##
## LEF for PtnCells ;
## created by Innovus v15.23-s045_1 on Tue Mar 10 18:08:15 2026
##

VERSION 5.8 ;

BUSBITCHARS "[]" ;
DIVIDERCHAR "/" ;

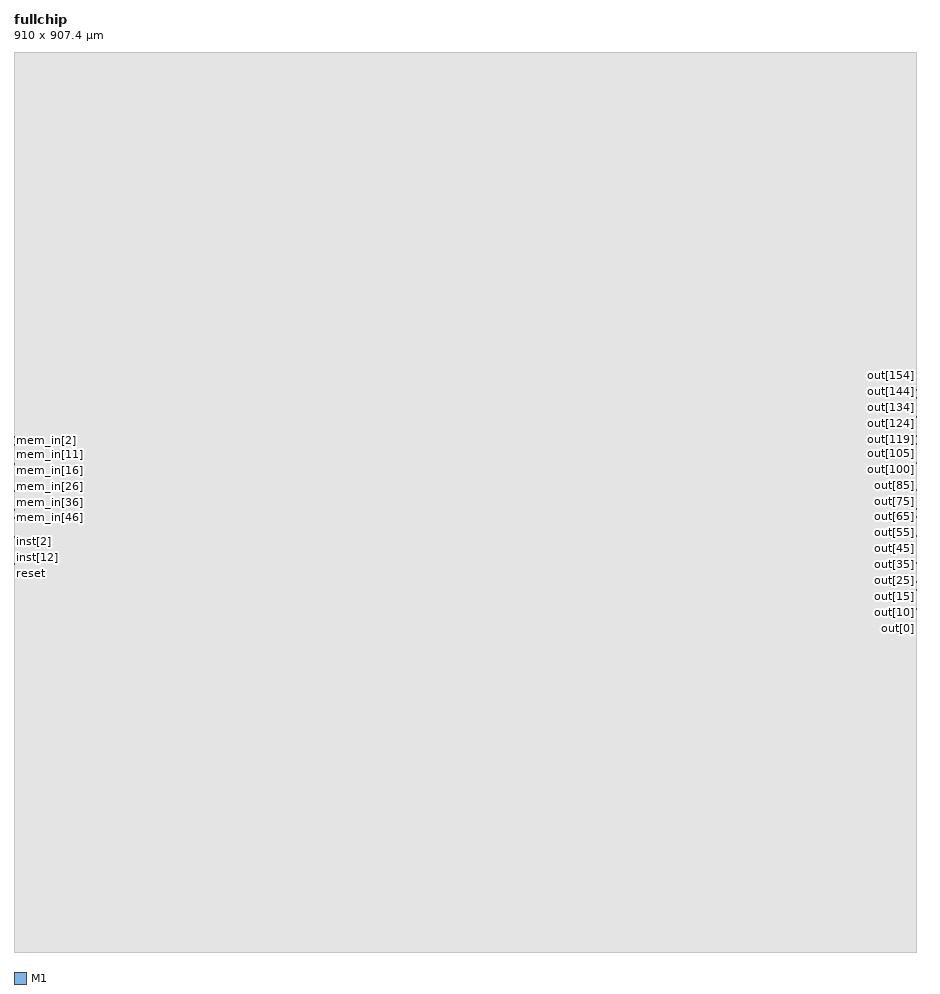
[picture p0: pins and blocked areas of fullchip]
MACRO fullchip
  CLASS BLOCK ;
  SIZE 910.0000 BY 907.4000 ;
  FOREIGN fullchip 0.0000 0.0000 ;
  ORIGIN 0 0 ;
  SYMMETRY X Y R90 ;
  PIN clk
    DIRECTION INPUT ;
    USE SIGNAL ;
    PORT
      LAYER M1 ;
        RECT 0.0000 387.9550 0.4700 388.0450 ;
    END
  END clk
  PIN mem_in[63]
    DIRECTION INPUT ;
    USE SIGNAL ;
    PORT
      LAYER M1 ;
        RECT 0.0000 418.3550 0.4700 418.4450 ;
    END
  END mem_in[63]
  PIN mem_in[62]
    DIRECTION INPUT ;
    USE SIGNAL ;
    PORT
      LAYER M1 ;
        RECT 0.0000 419.9550 0.4700 420.0450 ;
    END
  END mem_in[62]
  PIN mem_in[61]
    DIRECTION INPUT ;
    USE SIGNAL ;
    PORT
      LAYER M1 ;
        RECT 0.0000 421.5550 0.4700 421.6450 ;
    END
  END mem_in[61]
  PIN mem_in[60]
    DIRECTION INPUT ;
    USE SIGNAL ;
    PORT
      LAYER M1 ;
        RECT 0.0000 423.1550 0.4700 423.2450 ;
    END
  END mem_in[60]
  PIN mem_in[59]
    DIRECTION INPUT ;
    USE SIGNAL ;
    PORT
      LAYER M1 ;
        RECT 0.0000 424.7550 0.4700 424.8450 ;
    END
  END mem_in[59]
  PIN mem_in[58]
    DIRECTION INPUT ;
    USE SIGNAL ;
    PORT
      LAYER M1 ;
        RECT 0.0000 426.3550 0.4700 426.4450 ;
    END
  END mem_in[58]
  PIN mem_in[57]
    DIRECTION INPUT ;
    USE SIGNAL ;
    PORT
      LAYER M1 ;
        RECT 0.0000 427.9550 0.4700 428.0450 ;
    END
  END mem_in[57]
  PIN mem_in[56]
    DIRECTION INPUT ;
    USE SIGNAL ;
    PORT
      LAYER M1 ;
        RECT 0.0000 429.5550 0.4700 429.6450 ;
    END
  END mem_in[56]
  PIN mem_in[55]
    DIRECTION INPUT ;
    USE SIGNAL ;
    PORT
      LAYER M1 ;
        RECT 0.0000 431.1550 0.4700 431.2450 ;
    END
  END mem_in[55]
  PIN mem_in[54]
    DIRECTION INPUT ;
    USE SIGNAL ;
    PORT
      LAYER M1 ;
        RECT 0.0000 432.7550 0.4700 432.8450 ;
    END
  END mem_in[54]
  PIN mem_in[53]
    DIRECTION INPUT ;
    USE SIGNAL ;
    PORT
      LAYER M1 ;
        RECT 0.0000 434.3550 0.4700 434.4450 ;
    END
  END mem_in[53]
  PIN mem_in[52]
    DIRECTION INPUT ;
    USE SIGNAL ;
    PORT
      LAYER M1 ;
        RECT 0.0000 435.9550 0.4700 436.0450 ;
    END
  END mem_in[52]
  PIN mem_in[51]
    DIRECTION INPUT ;
    USE SIGNAL ;
    PORT
      LAYER M1 ;
        RECT 0.0000 437.5550 0.4700 437.6450 ;
    END
  END mem_in[51]
  PIN mem_in[50]
    DIRECTION INPUT ;
    USE SIGNAL ;
    PORT
      LAYER M1 ;
        RECT 0.0000 439.1550 0.4700 439.2450 ;
    END
  END mem_in[50]
  PIN mem_in[49]
    DIRECTION INPUT ;
    USE SIGNAL ;
    PORT
      LAYER M1 ;
        RECT 0.0000 440.7550 0.4700 440.8450 ;
    END
  END mem_in[49]
  PIN mem_in[48]
    DIRECTION INPUT ;
    USE SIGNAL ;
    PORT
      LAYER M1 ;
        RECT 0.0000 442.3550 0.4700 442.4450 ;
    END
  END mem_in[48]
  PIN mem_in[47]
    DIRECTION INPUT ;
    USE SIGNAL ;
    PORT
      LAYER M1 ;
        RECT 0.0000 443.9550 0.4700 444.0450 ;
    END
  END mem_in[47]
  PIN mem_in[46]
    DIRECTION INPUT ;
    USE SIGNAL ;
    PORT
      LAYER M1 ;
        RECT 0.0000 445.5550 0.4700 445.6450 ;
    END
  END mem_in[46]
  PIN mem_in[45]
    DIRECTION INPUT ;
    USE SIGNAL ;
    PORT
      LAYER M1 ;
        RECT 0.0000 447.1550 0.4700 447.2450 ;
    END
  END mem_in[45]
  PIN mem_in[44]
    DIRECTION INPUT ;
    USE SIGNAL ;
    PORT
      LAYER M1 ;
        RECT 0.0000 448.7550 0.4700 448.8450 ;
    END
  END mem_in[44]
  PIN mem_in[43]
    DIRECTION INPUT ;
    USE SIGNAL ;
    PORT
      LAYER M1 ;
        RECT 0.0000 450.3550 0.4700 450.4450 ;
    END
  END mem_in[43]
  PIN mem_in[42]
    DIRECTION INPUT ;
    USE SIGNAL ;
    PORT
      LAYER M1 ;
        RECT 0.0000 451.9550 0.4700 452.0450 ;
    END
  END mem_in[42]
  PIN mem_in[41]
    DIRECTION INPUT ;
    USE SIGNAL ;
    PORT
      LAYER M1 ;
        RECT 0.0000 453.5550 0.4700 453.6450 ;
    END
  END mem_in[41]
  PIN mem_in[40]
    DIRECTION INPUT ;
    USE SIGNAL ;
    PORT
      LAYER M1 ;
        RECT 0.0000 455.1550 0.4700 455.2450 ;
    END
  END mem_in[40]
  PIN mem_in[39]
    DIRECTION INPUT ;
    USE SIGNAL ;
    PORT
      LAYER M1 ;
        RECT 0.0000 456.7550 0.4700 456.8450 ;
    END
  END mem_in[39]
  PIN mem_in[38]
    DIRECTION INPUT ;
    USE SIGNAL ;
    PORT
      LAYER M1 ;
        RECT 0.0000 458.3550 0.4700 458.4450 ;
    END
  END mem_in[38]
  PIN mem_in[37]
    DIRECTION INPUT ;
    USE SIGNAL ;
    PORT
      LAYER M1 ;
        RECT 0.0000 459.9550 0.4700 460.0450 ;
    END
  END mem_in[37]
  PIN mem_in[36]
    DIRECTION INPUT ;
    USE SIGNAL ;
    PORT
      LAYER M1 ;
        RECT 0.0000 461.5550 0.4700 461.6450 ;
    END
  END mem_in[36]
  PIN mem_in[35]
    DIRECTION INPUT ;
    USE SIGNAL ;
    PORT
      LAYER M1 ;
        RECT 0.0000 463.1550 0.4700 463.2450 ;
    END
  END mem_in[35]
  PIN mem_in[34]
    DIRECTION INPUT ;
    USE SIGNAL ;
    PORT
      LAYER M1 ;
        RECT 0.0000 464.7550 0.4700 464.8450 ;
    END
  END mem_in[34]
  PIN mem_in[33]
    DIRECTION INPUT ;
    USE SIGNAL ;
    PORT
      LAYER M1 ;
        RECT 0.0000 466.3550 0.4700 466.4450 ;
    END
  END mem_in[33]
  PIN mem_in[32]
    DIRECTION INPUT ;
    USE SIGNAL ;
    PORT
      LAYER M1 ;
        RECT 0.0000 467.9550 0.4700 468.0450 ;
    END
  END mem_in[32]
  PIN mem_in[31]
    DIRECTION INPUT ;
    USE SIGNAL ;
    PORT
      LAYER M1 ;
        RECT 0.0000 469.5550 0.4700 469.6450 ;
    END
  END mem_in[31]
  PIN mem_in[30]
    DIRECTION INPUT ;
    USE SIGNAL ;
    PORT
      LAYER M1 ;
        RECT 0.0000 471.1550 0.4700 471.2450 ;
    END
  END mem_in[30]
  PIN mem_in[29]
    DIRECTION INPUT ;
    USE SIGNAL ;
    PORT
      LAYER M1 ;
        RECT 0.0000 472.7550 0.4700 472.8450 ;
    END
  END mem_in[29]
  PIN mem_in[28]
    DIRECTION INPUT ;
    USE SIGNAL ;
    PORT
      LAYER M1 ;
        RECT 0.0000 474.3550 0.4700 474.4450 ;
    END
  END mem_in[28]
  PIN mem_in[27]
    DIRECTION INPUT ;
    USE SIGNAL ;
    PORT
      LAYER M1 ;
        RECT 0.0000 475.9550 0.4700 476.0450 ;
    END
  END mem_in[27]
  PIN mem_in[26]
    DIRECTION INPUT ;
    USE SIGNAL ;
    PORT
      LAYER M1 ;
        RECT 0.0000 477.5550 0.4700 477.6450 ;
    END
  END mem_in[26]
  PIN mem_in[25]
    DIRECTION INPUT ;
    USE SIGNAL ;
    PORT
      LAYER M1 ;
        RECT 0.0000 479.1550 0.4700 479.2450 ;
    END
  END mem_in[25]
  PIN mem_in[24]
    DIRECTION INPUT ;
    USE SIGNAL ;
    PORT
      LAYER M1 ;
        RECT 0.0000 480.7550 0.4700 480.8450 ;
    END
  END mem_in[24]
  PIN mem_in[23]
    DIRECTION INPUT ;
    USE SIGNAL ;
    PORT
      LAYER M1 ;
        RECT 0.0000 482.3550 0.4700 482.4450 ;
    END
  END mem_in[23]
  PIN mem_in[22]
    DIRECTION INPUT ;
    USE SIGNAL ;
    PORT
      LAYER M1 ;
        RECT 0.0000 483.9550 0.4700 484.0450 ;
    END
  END mem_in[22]
  PIN mem_in[21]
    DIRECTION INPUT ;
    USE SIGNAL ;
    PORT
      LAYER M1 ;
        RECT 0.0000 485.5550 0.4700 485.6450 ;
    END
  END mem_in[21]
  PIN mem_in[20]
    DIRECTION INPUT ;
    USE SIGNAL ;
    PORT
      LAYER M1 ;
        RECT 0.0000 487.1550 0.4700 487.2450 ;
    END
  END mem_in[20]
  PIN mem_in[19]
    DIRECTION INPUT ;
    USE SIGNAL ;
    PORT
      LAYER M1 ;
        RECT 0.0000 488.7550 0.4700 488.8450 ;
    END
  END mem_in[19]
  PIN mem_in[18]
    DIRECTION INPUT ;
    USE SIGNAL ;
    PORT
      LAYER M1 ;
        RECT 0.0000 490.3550 0.4700 490.4450 ;
    END
  END mem_in[18]
  PIN mem_in[17]
    DIRECTION INPUT ;
    USE SIGNAL ;
    PORT
      LAYER M1 ;
        RECT 0.0000 491.9550 0.4700 492.0450 ;
    END
  END mem_in[17]
  PIN mem_in[16]
    DIRECTION INPUT ;
    USE SIGNAL ;
    PORT
      LAYER M1 ;
        RECT 0.0000 493.5550 0.4700 493.6450 ;
    END
  END mem_in[16]
  PIN mem_in[15]
    DIRECTION INPUT ;
    USE SIGNAL ;
    PORT
      LAYER M1 ;
        RECT 0.0000 495.1550 0.4700 495.2450 ;
    END
  END mem_in[15]
  PIN mem_in[14]
    DIRECTION INPUT ;
    USE SIGNAL ;
    PORT
      LAYER M1 ;
        RECT 0.0000 496.7550 0.4700 496.8450 ;
    END
  END mem_in[14]
  PIN mem_in[13]
    DIRECTION INPUT ;
    USE SIGNAL ;
    PORT
      LAYER M1 ;
        RECT 0.0000 498.3550 0.4700 498.4450 ;
    END
  END mem_in[13]
  PIN mem_in[12]
    DIRECTION INPUT ;
    USE SIGNAL ;
    PORT
      LAYER M1 ;
        RECT 0.0000 499.9550 0.4700 500.0450 ;
    END
  END mem_in[12]
  PIN mem_in[11]
    DIRECTION INPUT ;
    USE SIGNAL ;
    PORT
      LAYER M1 ;
        RECT 0.0000 501.5550 0.4700 501.6450 ;
    END
  END mem_in[11]
  PIN mem_in[10]
    DIRECTION INPUT ;
    USE SIGNAL ;
    PORT
      LAYER M1 ;
        RECT 0.0000 503.1550 0.4700 503.2450 ;
    END
  END mem_in[10]
  PIN mem_in[9]
    DIRECTION INPUT ;
    USE SIGNAL ;
    PORT
      LAYER M1 ;
        RECT 0.0000 504.7550 0.4700 504.8450 ;
    END
  END mem_in[9]
  PIN mem_in[8]
    DIRECTION INPUT ;
    USE SIGNAL ;
    PORT
      LAYER M1 ;
        RECT 0.0000 506.3550 0.4700 506.4450 ;
    END
  END mem_in[8]
  PIN mem_in[7]
    DIRECTION INPUT ;
    USE SIGNAL ;
    PORT
      LAYER M1 ;
        RECT 0.0000 507.9550 0.4700 508.0450 ;
    END
  END mem_in[7]
  PIN mem_in[6]
    DIRECTION INPUT ;
    USE SIGNAL ;
    PORT
      LAYER M1 ;
        RECT 0.0000 509.5550 0.4700 509.6450 ;
    END
  END mem_in[6]
  PIN mem_in[5]
    DIRECTION INPUT ;
    USE SIGNAL ;
    PORT
      LAYER M1 ;
        RECT 0.0000 511.1550 0.4700 511.2450 ;
    END
  END mem_in[5]
  PIN mem_in[4]
    DIRECTION INPUT ;
    USE SIGNAL ;
    PORT
      LAYER M1 ;
        RECT 0.0000 512.7550 0.4700 512.8450 ;
    END
  END mem_in[4]
  PIN mem_in[3]
    DIRECTION INPUT ;
    USE SIGNAL ;
    PORT
      LAYER M1 ;
        RECT 0.0000 514.3550 0.4700 514.4450 ;
    END
  END mem_in[3]
  PIN mem_in[2]
    DIRECTION INPUT ;
    USE SIGNAL ;
    PORT
      LAYER M1 ;
        RECT 0.0000 515.9550 0.4700 516.0450 ;
    END
  END mem_in[2]
  PIN mem_in[1]
    DIRECTION INPUT ;
    USE SIGNAL ;
    PORT
      LAYER M1 ;
        RECT 0.0000 517.5550 0.4700 517.6450 ;
    END
  END mem_in[1]
  PIN mem_in[0]
    DIRECTION INPUT ;
    USE SIGNAL ;
    PORT
      LAYER M1 ;
        RECT 0.0000 519.1550 0.4700 519.2450 ;
    END
  END mem_in[0]
  PIN inst[16]
    DIRECTION INPUT ;
    USE SIGNAL ;
    PORT
      LAYER M1 ;
        RECT 0.0000 391.1550 0.4700 391.2450 ;
    END
  END inst[16]
  PIN inst[15]
    DIRECTION INPUT ;
    USE SIGNAL ;
    PORT
      LAYER M1 ;
        RECT 0.0000 392.7550 0.4700 392.8450 ;
    END
  END inst[15]
  PIN inst[14]
    DIRECTION INPUT ;
    USE SIGNAL ;
    PORT
      LAYER M1 ;
        RECT 0.0000 394.3550 0.4700 394.4450 ;
    END
  END inst[14]
  PIN inst[13]
    DIRECTION INPUT ;
    USE SIGNAL ;
    PORT
      LAYER M1 ;
        RECT 0.0000 395.9550 0.4700 396.0450 ;
    END
  END inst[13]
  PIN inst[12]
    DIRECTION INPUT ;
    USE SIGNAL ;
    PORT
      LAYER M1 ;
        RECT 0.0000 397.5550 0.4700 397.6450 ;
    END
  END inst[12]
  PIN inst[11]
    DIRECTION INPUT ;
    USE SIGNAL ;
    PORT
      LAYER M1 ;
        RECT 0.0000 399.1550 0.4700 399.2450 ;
    END
  END inst[11]
  PIN inst[10]
    DIRECTION INPUT ;
    USE SIGNAL ;
    PORT
      LAYER M1 ;
        RECT 0.0000 400.7550 0.4700 400.8450 ;
    END
  END inst[10]
  PIN inst[9]
    DIRECTION INPUT ;
    USE SIGNAL ;
    PORT
      LAYER M1 ;
        RECT 0.0000 402.3550 0.4700 402.4450 ;
    END
  END inst[9]
  PIN inst[8]
    DIRECTION INPUT ;
    USE SIGNAL ;
    PORT
      LAYER M1 ;
        RECT 0.0000 403.9550 0.4700 404.0450 ;
    END
  END inst[8]
  PIN inst[7]
    DIRECTION INPUT ;
    USE SIGNAL ;
    PORT
      LAYER M1 ;
        RECT 0.0000 405.5550 0.4700 405.6450 ;
    END
  END inst[7]
  PIN inst[6]
    DIRECTION INPUT ;
    USE SIGNAL ;
    PORT
      LAYER M1 ;
        RECT 0.0000 407.1550 0.4700 407.2450 ;
    END
  END inst[6]
  PIN inst[5]
    DIRECTION INPUT ;
    USE SIGNAL ;
    PORT
      LAYER M1 ;
        RECT 0.0000 408.7550 0.4700 408.8450 ;
    END
  END inst[5]
  PIN inst[4]
    DIRECTION INPUT ;
    USE SIGNAL ;
    PORT
      LAYER M1 ;
        RECT 0.0000 410.3550 0.4700 410.4450 ;
    END
  END inst[4]
  PIN inst[3]
    DIRECTION INPUT ;
    USE SIGNAL ;
    PORT
      LAYER M1 ;
        RECT 0.0000 411.9550 0.4700 412.0450 ;
    END
  END inst[3]
  PIN inst[2]
    DIRECTION INPUT ;
    USE SIGNAL ;
    PORT
      LAYER M1 ;
        RECT 0.0000 413.5550 0.4700 413.6450 ;
    END
  END inst[2]
  PIN inst[1]
    DIRECTION INPUT ;
    USE SIGNAL ;
    PORT
      LAYER M1 ;
        RECT 0.0000 415.1550 0.4700 415.2450 ;
    END
  END inst[1]
  PIN inst[0]
    DIRECTION INPUT ;
    USE SIGNAL ;
    PORT
      LAYER M1 ;
        RECT 0.0000 416.7550 0.4700 416.8450 ;
    END
  END inst[0]
  PIN out[159]
    DIRECTION OUTPUT ;
    USE SIGNAL ;
    PORT
      LAYER M1 ;
        RECT 909.5300 580.9550 910.0000 581.0450 ;
    END
  END out[159]
  PIN out[158]
    DIRECTION OUTPUT ;
    USE SIGNAL ;
    PORT
      LAYER M1 ;
        RECT 909.5300 579.3550 910.0000 579.4450 ;
    END
  END out[158]
  PIN out[157]
    DIRECTION OUTPUT ;
    USE SIGNAL ;
    PORT
      LAYER M1 ;
        RECT 909.5300 577.7550 910.0000 577.8450 ;
    END
  END out[157]
  PIN out[156]
    DIRECTION OUTPUT ;
    USE SIGNAL ;
    PORT
      LAYER M1 ;
        RECT 909.5300 576.1550 910.0000 576.2450 ;
    END
  END out[156]
  PIN out[155]
    DIRECTION OUTPUT ;
    USE SIGNAL ;
    PORT
      LAYER M1 ;
        RECT 909.5300 574.5550 910.0000 574.6450 ;
    END
  END out[155]
  PIN out[154]
    DIRECTION OUTPUT ;
    USE SIGNAL ;
    PORT
      LAYER M1 ;
        RECT 909.5300 572.9550 910.0000 573.0450 ;
    END
  END out[154]
  PIN out[153]
    DIRECTION OUTPUT ;
    USE SIGNAL ;
    PORT
      LAYER M1 ;
        RECT 909.5300 571.3550 910.0000 571.4450 ;
    END
  END out[153]
  PIN out[152]
    DIRECTION OUTPUT ;
    USE SIGNAL ;
    PORT
      LAYER M1 ;
        RECT 909.5300 569.7550 910.0000 569.8450 ;
    END
  END out[152]
  PIN out[151]
    DIRECTION OUTPUT ;
    USE SIGNAL ;
    PORT
      LAYER M1 ;
        RECT 909.5300 568.1550 910.0000 568.2450 ;
    END
  END out[151]
  PIN out[150]
    DIRECTION OUTPUT ;
    USE SIGNAL ;
    PORT
      LAYER M1 ;
        RECT 909.5300 566.5550 910.0000 566.6450 ;
    END
  END out[150]
  PIN out[149]
    DIRECTION OUTPUT ;
    USE SIGNAL ;
    PORT
      LAYER M1 ;
        RECT 909.5300 564.9550 910.0000 565.0450 ;
    END
  END out[149]
  PIN out[148]
    DIRECTION OUTPUT ;
    USE SIGNAL ;
    PORT
      LAYER M1 ;
        RECT 909.5300 563.3550 910.0000 563.4450 ;
    END
  END out[148]
  PIN out[147]
    DIRECTION OUTPUT ;
    USE SIGNAL ;
    PORT
      LAYER M1 ;
        RECT 909.5300 561.7550 910.0000 561.8450 ;
    END
  END out[147]
  PIN out[146]
    DIRECTION OUTPUT ;
    USE SIGNAL ;
    PORT
      LAYER M1 ;
        RECT 909.5300 560.1550 910.0000 560.2450 ;
    END
  END out[146]
  PIN out[145]
    DIRECTION OUTPUT ;
    USE SIGNAL ;
    PORT
      LAYER M1 ;
        RECT 909.5300 558.5550 910.0000 558.6450 ;
    END
  END out[145]
  PIN out[144]
    DIRECTION OUTPUT ;
    USE SIGNAL ;
    PORT
      LAYER M1 ;
        RECT 909.5300 556.9550 910.0000 557.0450 ;
    END
  END out[144]
  PIN out[143]
    DIRECTION OUTPUT ;
    USE SIGNAL ;
    PORT
      LAYER M1 ;
        RECT 909.5300 555.3550 910.0000 555.4450 ;
    END
  END out[143]
  PIN out[142]
    DIRECTION OUTPUT ;
    USE SIGNAL ;
    PORT
      LAYER M1 ;
        RECT 909.5300 553.7550 910.0000 553.8450 ;
    END
  END out[142]
  PIN out[141]
    DIRECTION OUTPUT ;
    USE SIGNAL ;
    PORT
      LAYER M1 ;
        RECT 909.5300 552.1550 910.0000 552.2450 ;
    END
  END out[141]
  PIN out[140]
    DIRECTION OUTPUT ;
    USE SIGNAL ;
    PORT
      LAYER M1 ;
        RECT 909.5300 550.5550 910.0000 550.6450 ;
    END
  END out[140]
  PIN out[139]
    DIRECTION OUTPUT ;
    USE SIGNAL ;
    PORT
      LAYER M1 ;
        RECT 909.5300 548.9550 910.0000 549.0450 ;
    END
  END out[139]
  PIN out[138]
    DIRECTION OUTPUT ;
    USE SIGNAL ;
    PORT
      LAYER M1 ;
        RECT 909.5300 547.3550 910.0000 547.4450 ;
    END
  END out[138]
  PIN out[137]
    DIRECTION OUTPUT ;
    USE SIGNAL ;
    PORT
      LAYER M1 ;
        RECT 909.5300 545.7550 910.0000 545.8450 ;
    END
  END out[137]
  PIN out[136]
    DIRECTION OUTPUT ;
    USE SIGNAL ;
    PORT
      LAYER M1 ;
        RECT 909.5300 544.1550 910.0000 544.2450 ;
    END
  END out[136]
  PIN out[135]
    DIRECTION OUTPUT ;
    USE SIGNAL ;
    PORT
      LAYER M1 ;
        RECT 909.5300 542.5550 910.0000 542.6450 ;
    END
  END out[135]
  PIN out[134]
    DIRECTION OUTPUT ;
    USE SIGNAL ;
    PORT
      LAYER M1 ;
        RECT 909.5300 540.9550 910.0000 541.0450 ;
    END
  END out[134]
  PIN out[133]
    DIRECTION OUTPUT ;
    USE SIGNAL ;
    PORT
      LAYER M1 ;
        RECT 909.5300 539.3550 910.0000 539.4450 ;
    END
  END out[133]
  PIN out[132]
    DIRECTION OUTPUT ;
    USE SIGNAL ;
    PORT
      LAYER M1 ;
        RECT 909.5300 537.7550 910.0000 537.8450 ;
    END
  END out[132]
  PIN out[131]
    DIRECTION OUTPUT ;
    USE SIGNAL ;
    PORT
      LAYER M1 ;
        RECT 909.5300 536.1550 910.0000 536.2450 ;
    END
  END out[131]
  PIN out[130]
    DIRECTION OUTPUT ;
    USE SIGNAL ;
    PORT
      LAYER M1 ;
        RECT 909.5300 534.5550 910.0000 534.6450 ;
    END
  END out[130]
  PIN out[129]
    DIRECTION OUTPUT ;
    USE SIGNAL ;
    PORT
      LAYER M1 ;
        RECT 909.5300 532.9550 910.0000 533.0450 ;
    END
  END out[129]
  PIN out[128]
    DIRECTION OUTPUT ;
    USE SIGNAL ;
    PORT
      LAYER M1 ;
        RECT 909.5300 531.3550 910.0000 531.4450 ;
    END
  END out[128]
  PIN out[127]
    DIRECTION OUTPUT ;
    USE SIGNAL ;
    PORT
      LAYER M1 ;
        RECT 909.5300 529.7550 910.0000 529.8450 ;
    END
  END out[127]
  PIN out[126]
    DIRECTION OUTPUT ;
    USE SIGNAL ;
    PORT
      LAYER M1 ;
        RECT 909.5300 528.1550 910.0000 528.2450 ;
    END
  END out[126]
  PIN out[125]
    DIRECTION OUTPUT ;
    USE SIGNAL ;
    PORT
      LAYER M1 ;
        RECT 909.5300 526.5550 910.0000 526.6450 ;
    END
  END out[125]
  PIN out[124]
    DIRECTION OUTPUT ;
    USE SIGNAL ;
    PORT
      LAYER M1 ;
        RECT 909.5300 524.9550 910.0000 525.0450 ;
    END
  END out[124]
  PIN out[123]
    DIRECTION OUTPUT ;
    USE SIGNAL ;
    PORT
      LAYER M1 ;
        RECT 909.5300 523.3550 910.0000 523.4450 ;
    END
  END out[123]
  PIN out[122]
    DIRECTION OUTPUT ;
    USE SIGNAL ;
    PORT
      LAYER M1 ;
        RECT 909.5300 521.7550 910.0000 521.8450 ;
    END
  END out[122]
  PIN out[121]
    DIRECTION OUTPUT ;
    USE SIGNAL ;
    PORT
      LAYER M1 ;
        RECT 909.5300 520.1550 910.0000 520.2450 ;
    END
  END out[121]
  PIN out[120]
    DIRECTION OUTPUT ;
    USE SIGNAL ;
    PORT
      LAYER M1 ;
        RECT 909.5300 518.5550 910.0000 518.6450 ;
    END
  END out[120]
  PIN out[119]
    DIRECTION OUTPUT ;
    USE SIGNAL ;
    PORT
      LAYER M1 ;
        RECT 909.5300 516.9550 910.0000 517.0450 ;
    END
  END out[119]
  PIN out[118]
    DIRECTION OUTPUT ;
    USE SIGNAL ;
    PORT
      LAYER M1 ;
        RECT 909.5300 515.3550 910.0000 515.4450 ;
    END
  END out[118]
  PIN out[117]
    DIRECTION OUTPUT ;
    USE SIGNAL ;
    PORT
      LAYER M1 ;
        RECT 909.5300 513.7550 910.0000 513.8450 ;
    END
  END out[117]
  PIN out[116]
    DIRECTION OUTPUT ;
    USE SIGNAL ;
    PORT
      LAYER M1 ;
        RECT 909.5300 512.1550 910.0000 512.2450 ;
    END
  END out[116]
  PIN out[115]
    DIRECTION OUTPUT ;
    USE SIGNAL ;
    PORT
      LAYER M1 ;
        RECT 909.5300 510.5550 910.0000 510.6450 ;
    END
  END out[115]
  PIN out[114]
    DIRECTION OUTPUT ;
    USE SIGNAL ;
    PORT
      LAYER M1 ;
        RECT 909.5300 508.9550 910.0000 509.0450 ;
    END
  END out[114]
  PIN out[113]
    DIRECTION OUTPUT ;
    USE SIGNAL ;
    PORT
      LAYER M1 ;
        RECT 909.5300 507.3550 910.0000 507.4450 ;
    END
  END out[113]
  PIN out[112]
    DIRECTION OUTPUT ;
    USE SIGNAL ;
    PORT
      LAYER M1 ;
        RECT 909.5300 505.7550 910.0000 505.8450 ;
    END
  END out[112]
  PIN out[111]
    DIRECTION OUTPUT ;
    USE SIGNAL ;
    PORT
      LAYER M1 ;
        RECT 909.5300 504.1550 910.0000 504.2450 ;
    END
  END out[111]
  PIN out[110]
    DIRECTION OUTPUT ;
    USE SIGNAL ;
    PORT
      LAYER M1 ;
        RECT 909.5300 502.5550 910.0000 502.6450 ;
    END
  END out[110]
  PIN out[109]
    DIRECTION OUTPUT ;
    USE SIGNAL ;
    PORT
      LAYER M1 ;
        RECT 909.5300 500.9550 910.0000 501.0450 ;
    END
  END out[109]
  PIN out[108]
    DIRECTION OUTPUT ;
    USE SIGNAL ;
    PORT
      LAYER M1 ;
        RECT 909.5300 499.3550 910.0000 499.4450 ;
    END
  END out[108]
  PIN out[107]
    DIRECTION OUTPUT ;
    USE SIGNAL ;
    PORT
      LAYER M1 ;
        RECT 909.5300 497.7550 910.0000 497.8450 ;
    END
  END out[107]
  PIN out[106]
    DIRECTION OUTPUT ;
    USE SIGNAL ;
    PORT
      LAYER M1 ;
        RECT 909.5300 496.1550 910.0000 496.2450 ;
    END
  END out[106]
  PIN out[105]
    DIRECTION OUTPUT ;
    USE SIGNAL ;
    PORT
      LAYER M1 ;
        RECT 909.5300 494.5550 910.0000 494.6450 ;
    END
  END out[105]
  PIN out[104]
    DIRECTION OUTPUT ;
    USE SIGNAL ;
    PORT
      LAYER M1 ;
        RECT 909.5300 492.9550 910.0000 493.0450 ;
    END
  END out[104]
  PIN out[103]
    DIRECTION OUTPUT ;
    USE SIGNAL ;
    PORT
      LAYER M1 ;
        RECT 909.5300 491.3550 910.0000 491.4450 ;
    END
  END out[103]
  PIN out[102]
    DIRECTION OUTPUT ;
    USE SIGNAL ;
    PORT
      LAYER M1 ;
        RECT 909.5300 489.7550 910.0000 489.8450 ;
    END
  END out[102]
  PIN out[101]
    DIRECTION OUTPUT ;
    USE SIGNAL ;
    PORT
      LAYER M1 ;
        RECT 909.5300 488.1550 910.0000 488.2450 ;
    END
  END out[101]
  PIN out[100]
    DIRECTION OUTPUT ;
    USE SIGNAL ;
    PORT
      LAYER M1 ;
        RECT 909.5300 486.5550 910.0000 486.6450 ;
    END
  END out[100]
  PIN out[99]
    DIRECTION OUTPUT ;
    USE SIGNAL ;
    PORT
      LAYER M1 ;
        RECT 909.5300 484.9550 910.0000 485.0450 ;
    END
  END out[99]
  PIN out[98]
    DIRECTION OUTPUT ;
    USE SIGNAL ;
    PORT
      LAYER M1 ;
        RECT 909.5300 483.3550 910.0000 483.4450 ;
    END
  END out[98]
  PIN out[97]
    DIRECTION OUTPUT ;
    USE SIGNAL ;
    PORT
      LAYER M1 ;
        RECT 909.5300 481.7550 910.0000 481.8450 ;
    END
  END out[97]
  PIN out[96]
    DIRECTION OUTPUT ;
    USE SIGNAL ;
    PORT
      LAYER M1 ;
        RECT 909.5300 480.1550 910.0000 480.2450 ;
    END
  END out[96]
  PIN out[95]
    DIRECTION OUTPUT ;
    USE SIGNAL ;
    PORT
      LAYER M1 ;
        RECT 909.5300 478.5550 910.0000 478.6450 ;
    END
  END out[95]
  PIN out[94]
    DIRECTION OUTPUT ;
    USE SIGNAL ;
    PORT
      LAYER M1 ;
        RECT 909.5300 476.9550 910.0000 477.0450 ;
    END
  END out[94]
  PIN out[93]
    DIRECTION OUTPUT ;
    USE SIGNAL ;
    PORT
      LAYER M1 ;
        RECT 909.5300 475.3550 910.0000 475.4450 ;
    END
  END out[93]
  PIN out[92]
    DIRECTION OUTPUT ;
    USE SIGNAL ;
    PORT
      LAYER M1 ;
        RECT 909.5300 473.7550 910.0000 473.8450 ;
    END
  END out[92]
  PIN out[91]
    DIRECTION OUTPUT ;
    USE SIGNAL ;
    PORT
      LAYER M1 ;
        RECT 909.5300 472.1550 910.0000 472.2450 ;
    END
  END out[91]
  PIN out[90]
    DIRECTION OUTPUT ;
    USE SIGNAL ;
    PORT
      LAYER M1 ;
        RECT 909.5300 470.5550 910.0000 470.6450 ;
    END
  END out[90]
  PIN out[89]
    DIRECTION OUTPUT ;
    USE SIGNAL ;
    PORT
      LAYER M1 ;
        RECT 909.5300 468.9550 910.0000 469.0450 ;
    END
  END out[89]
  PIN out[88]
    DIRECTION OUTPUT ;
    USE SIGNAL ;
    PORT
      LAYER M1 ;
        RECT 909.5300 467.3550 910.0000 467.4450 ;
    END
  END out[88]
  PIN out[87]
    DIRECTION OUTPUT ;
    USE SIGNAL ;
    PORT
      LAYER M1 ;
        RECT 909.5300 465.7550 910.0000 465.8450 ;
    END
  END out[87]
  PIN out[86]
    DIRECTION OUTPUT ;
    USE SIGNAL ;
    PORT
      LAYER M1 ;
        RECT 909.5300 464.1550 910.0000 464.2450 ;
    END
  END out[86]
  PIN out[85]
    DIRECTION OUTPUT ;
    USE SIGNAL ;
    PORT
      LAYER M1 ;
        RECT 909.5300 462.5550 910.0000 462.6450 ;
    END
  END out[85]
  PIN out[84]
    DIRECTION OUTPUT ;
    USE SIGNAL ;
    PORT
      LAYER M1 ;
        RECT 909.5300 460.9550 910.0000 461.0450 ;
    END
  END out[84]
  PIN out[83]
    DIRECTION OUTPUT ;
    USE SIGNAL ;
    PORT
      LAYER M1 ;
        RECT 909.5300 459.3550 910.0000 459.4450 ;
    END
  END out[83]
  PIN out[82]
    DIRECTION OUTPUT ;
    USE SIGNAL ;
    PORT
      LAYER M1 ;
        RECT 909.5300 457.7550 910.0000 457.8450 ;
    END
  END out[82]
  PIN out[81]
    DIRECTION OUTPUT ;
    USE SIGNAL ;
    PORT
      LAYER M1 ;
        RECT 909.5300 456.1550 910.0000 456.2450 ;
    END
  END out[81]
  PIN out[80]
    DIRECTION OUTPUT ;
    USE SIGNAL ;
    PORT
      LAYER M1 ;
        RECT 909.5300 454.5550 910.0000 454.6450 ;
    END
  END out[80]
  PIN out[79]
    DIRECTION OUTPUT ;
    USE SIGNAL ;
    PORT
      LAYER M1 ;
        RECT 909.5300 452.9550 910.0000 453.0450 ;
    END
  END out[79]
  PIN out[78]
    DIRECTION OUTPUT ;
    USE SIGNAL ;
    PORT
      LAYER M1 ;
        RECT 909.5300 451.3550 910.0000 451.4450 ;
    END
  END out[78]
  PIN out[77]
    DIRECTION OUTPUT ;
    USE SIGNAL ;
    PORT
      LAYER M1 ;
        RECT 909.5300 449.7550 910.0000 449.8450 ;
    END
  END out[77]
  PIN out[76]
    DIRECTION OUTPUT ;
    USE SIGNAL ;
    PORT
      LAYER M1 ;
        RECT 909.5300 448.1550 910.0000 448.2450 ;
    END
  END out[76]
  PIN out[75]
    DIRECTION OUTPUT ;
    USE SIGNAL ;
    PORT
      LAYER M1 ;
        RECT 909.5300 446.5550 910.0000 446.6450 ;
    END
  END out[75]
  PIN out[74]
    DIRECTION OUTPUT ;
    USE SIGNAL ;
    PORT
      LAYER M1 ;
        RECT 909.5300 444.9550 910.0000 445.0450 ;
    END
  END out[74]
  PIN out[73]
    DIRECTION OUTPUT ;
    USE SIGNAL ;
    PORT
      LAYER M1 ;
        RECT 909.5300 443.3550 910.0000 443.4450 ;
    END
  END out[73]
  PIN out[72]
    DIRECTION OUTPUT ;
    USE SIGNAL ;
    PORT
      LAYER M1 ;
        RECT 909.5300 441.7550 910.0000 441.8450 ;
    END
  END out[72]
  PIN out[71]
    DIRECTION OUTPUT ;
    USE SIGNAL ;
    PORT
      LAYER M1 ;
        RECT 909.5300 440.1550 910.0000 440.2450 ;
    END
  END out[71]
  PIN out[70]
    DIRECTION OUTPUT ;
    USE SIGNAL ;
    PORT
      LAYER M1 ;
        RECT 909.5300 438.5550 910.0000 438.6450 ;
    END
  END out[70]
  PIN out[69]
    DIRECTION OUTPUT ;
    USE SIGNAL ;
    PORT
      LAYER M1 ;
        RECT 909.5300 436.9550 910.0000 437.0450 ;
    END
  END out[69]
  PIN out[68]
    DIRECTION OUTPUT ;
    USE SIGNAL ;
    PORT
      LAYER M1 ;
        RECT 909.5300 435.3550 910.0000 435.4450 ;
    END
  END out[68]
  PIN out[67]
    DIRECTION OUTPUT ;
    USE SIGNAL ;
    PORT
      LAYER M1 ;
        RECT 909.5300 433.7550 910.0000 433.8450 ;
    END
  END out[67]
  PIN out[66]
    DIRECTION OUTPUT ;
    USE SIGNAL ;
    PORT
      LAYER M1 ;
        RECT 909.5300 432.1550 910.0000 432.2450 ;
    END
  END out[66]
  PIN out[65]
    DIRECTION OUTPUT ;
    USE SIGNAL ;
    PORT
      LAYER M1 ;
        RECT 909.5300 430.5550 910.0000 430.6450 ;
    END
  END out[65]
  PIN out[64]
    DIRECTION OUTPUT ;
    USE SIGNAL ;
    PORT
      LAYER M1 ;
        RECT 909.5300 428.9550 910.0000 429.0450 ;
    END
  END out[64]
  PIN out[63]
    DIRECTION OUTPUT ;
    USE SIGNAL ;
    PORT
      LAYER M1 ;
        RECT 909.5300 427.3550 910.0000 427.4450 ;
    END
  END out[63]
  PIN out[62]
    DIRECTION OUTPUT ;
    USE SIGNAL ;
    PORT
      LAYER M1 ;
        RECT 909.5300 425.7550 910.0000 425.8450 ;
    END
  END out[62]
  PIN out[61]
    DIRECTION OUTPUT ;
    USE SIGNAL ;
    PORT
      LAYER M1 ;
        RECT 909.5300 424.1550 910.0000 424.2450 ;
    END
  END out[61]
  PIN out[60]
    DIRECTION OUTPUT ;
    USE SIGNAL ;
    PORT
      LAYER M1 ;
        RECT 909.5300 422.5550 910.0000 422.6450 ;
    END
  END out[60]
  PIN out[59]
    DIRECTION OUTPUT ;
    USE SIGNAL ;
    PORT
      LAYER M1 ;
        RECT 909.5300 420.9550 910.0000 421.0450 ;
    END
  END out[59]
  PIN out[58]
    DIRECTION OUTPUT ;
    USE SIGNAL ;
    PORT
      LAYER M1 ;
        RECT 909.5300 419.3550 910.0000 419.4450 ;
    END
  END out[58]
  PIN out[57]
    DIRECTION OUTPUT ;
    USE SIGNAL ;
    PORT
      LAYER M1 ;
        RECT 909.5300 417.7550 910.0000 417.8450 ;
    END
  END out[57]
  PIN out[56]
    DIRECTION OUTPUT ;
    USE SIGNAL ;
    PORT
      LAYER M1 ;
        RECT 909.5300 416.1550 910.0000 416.2450 ;
    END
  END out[56]
  PIN out[55]
    DIRECTION OUTPUT ;
    USE SIGNAL ;
    PORT
      LAYER M1 ;
        RECT 909.5300 414.5550 910.0000 414.6450 ;
    END
  END out[55]
  PIN out[54]
    DIRECTION OUTPUT ;
    USE SIGNAL ;
    PORT
      LAYER M1 ;
        RECT 909.5300 412.9550 910.0000 413.0450 ;
    END
  END out[54]
  PIN out[53]
    DIRECTION OUTPUT ;
    USE SIGNAL ;
    PORT
      LAYER M1 ;
        RECT 909.5300 411.3550 910.0000 411.4450 ;
    END
  END out[53]
  PIN out[52]
    DIRECTION OUTPUT ;
    USE SIGNAL ;
    PORT
      LAYER M1 ;
        RECT 909.5300 409.7550 910.0000 409.8450 ;
    END
  END out[52]
  PIN out[51]
    DIRECTION OUTPUT ;
    USE SIGNAL ;
    PORT
      LAYER M1 ;
        RECT 909.5300 408.1550 910.0000 408.2450 ;
    END
  END out[51]
  PIN out[50]
    DIRECTION OUTPUT ;
    USE SIGNAL ;
    PORT
      LAYER M1 ;
        RECT 909.5300 406.5550 910.0000 406.6450 ;
    END
  END out[50]
  PIN out[49]
    DIRECTION OUTPUT ;
    USE SIGNAL ;
    PORT
      LAYER M1 ;
        RECT 909.5300 404.9550 910.0000 405.0450 ;
    END
  END out[49]
  PIN out[48]
    DIRECTION OUTPUT ;
    USE SIGNAL ;
    PORT
      LAYER M1 ;
        RECT 909.5300 403.3550 910.0000 403.4450 ;
    END
  END out[48]
  PIN out[47]
    DIRECTION OUTPUT ;
    USE SIGNAL ;
    PORT
      LAYER M1 ;
        RECT 909.5300 401.7550 910.0000 401.8450 ;
    END
  END out[47]
  PIN out[46]
    DIRECTION OUTPUT ;
    USE SIGNAL ;
    PORT
      LAYER M1 ;
        RECT 909.5300 400.1550 910.0000 400.2450 ;
    END
  END out[46]
  PIN out[45]
    DIRECTION OUTPUT ;
    USE SIGNAL ;
    PORT
      LAYER M1 ;
        RECT 909.5300 398.5550 910.0000 398.6450 ;
    END
  END out[45]
  PIN out[44]
    DIRECTION OUTPUT ;
    USE SIGNAL ;
    PORT
      LAYER M1 ;
        RECT 909.5300 396.9550 910.0000 397.0450 ;
    END
  END out[44]
  PIN out[43]
    DIRECTION OUTPUT ;
    USE SIGNAL ;
    PORT
      LAYER M1 ;
        RECT 909.5300 395.3550 910.0000 395.4450 ;
    END
  END out[43]
  PIN out[42]
    DIRECTION OUTPUT ;
    USE SIGNAL ;
    PORT
      LAYER M1 ;
        RECT 909.5300 393.7550 910.0000 393.8450 ;
    END
  END out[42]
  PIN out[41]
    DIRECTION OUTPUT ;
    USE SIGNAL ;
    PORT
      LAYER M1 ;
        RECT 909.5300 392.1550 910.0000 392.2450 ;
    END
  END out[41]
  PIN out[40]
    DIRECTION OUTPUT ;
    USE SIGNAL ;
    PORT
      LAYER M1 ;
        RECT 909.5300 390.5550 910.0000 390.6450 ;
    END
  END out[40]
  PIN out[39]
    DIRECTION OUTPUT ;
    USE SIGNAL ;
    PORT
      LAYER M1 ;
        RECT 909.5300 388.9550 910.0000 389.0450 ;
    END
  END out[39]
  PIN out[38]
    DIRECTION OUTPUT ;
    USE SIGNAL ;
    PORT
      LAYER M1 ;
        RECT 909.5300 387.3550 910.0000 387.4450 ;
    END
  END out[38]
  PIN out[37]
    DIRECTION OUTPUT ;
    USE SIGNAL ;
    PORT
      LAYER M1 ;
        RECT 909.5300 385.7550 910.0000 385.8450 ;
    END
  END out[37]
  PIN out[36]
    DIRECTION OUTPUT ;
    USE SIGNAL ;
    PORT
      LAYER M1 ;
        RECT 909.5300 384.1550 910.0000 384.2450 ;
    END
  END out[36]
  PIN out[35]
    DIRECTION OUTPUT ;
    USE SIGNAL ;
    PORT
      LAYER M1 ;
        RECT 909.5300 382.5550 910.0000 382.6450 ;
    END
  END out[35]
  PIN out[34]
    DIRECTION OUTPUT ;
    USE SIGNAL ;
    PORT
      LAYER M1 ;
        RECT 909.5300 380.9550 910.0000 381.0450 ;
    END
  END out[34]
  PIN out[33]
    DIRECTION OUTPUT ;
    USE SIGNAL ;
    PORT
      LAYER M1 ;
        RECT 909.5300 379.3550 910.0000 379.4450 ;
    END
  END out[33]
  PIN out[32]
    DIRECTION OUTPUT ;
    USE SIGNAL ;
    PORT
      LAYER M1 ;
        RECT 909.5300 377.7550 910.0000 377.8450 ;
    END
  END out[32]
  PIN out[31]
    DIRECTION OUTPUT ;
    USE SIGNAL ;
    PORT
      LAYER M1 ;
        RECT 909.5300 376.1550 910.0000 376.2450 ;
    END
  END out[31]
  PIN out[30]
    DIRECTION OUTPUT ;
    USE SIGNAL ;
    PORT
      LAYER M1 ;
        RECT 909.5300 374.5550 910.0000 374.6450 ;
    END
  END out[30]
  PIN out[29]
    DIRECTION OUTPUT ;
    USE SIGNAL ;
    PORT
      LAYER M1 ;
        RECT 909.5300 372.9550 910.0000 373.0450 ;
    END
  END out[29]
  PIN out[28]
    DIRECTION OUTPUT ;
    USE SIGNAL ;
    PORT
      LAYER M1 ;
        RECT 909.5300 371.3550 910.0000 371.4450 ;
    END
  END out[28]
  PIN out[27]
    DIRECTION OUTPUT ;
    USE SIGNAL ;
    PORT
      LAYER M1 ;
        RECT 909.5300 369.7550 910.0000 369.8450 ;
    END
  END out[27]
  PIN out[26]
    DIRECTION OUTPUT ;
    USE SIGNAL ;
    PORT
      LAYER M1 ;
        RECT 909.5300 368.1550 910.0000 368.2450 ;
    END
  END out[26]
  PIN out[25]
    DIRECTION OUTPUT ;
    USE SIGNAL ;
    PORT
      LAYER M1 ;
        RECT 909.5300 366.5550 910.0000 366.6450 ;
    END
  END out[25]
  PIN out[24]
    DIRECTION OUTPUT ;
    USE SIGNAL ;
    PORT
      LAYER M1 ;
        RECT 909.5300 364.9550 910.0000 365.0450 ;
    END
  END out[24]
  PIN out[23]
    DIRECTION OUTPUT ;
    USE SIGNAL ;
    PORT
      LAYER M1 ;
        RECT 909.5300 363.3550 910.0000 363.4450 ;
    END
  END out[23]
  PIN out[22]
    DIRECTION OUTPUT ;
    USE SIGNAL ;
    PORT
      LAYER M1 ;
        RECT 909.5300 361.7550 910.0000 361.8450 ;
    END
  END out[22]
  PIN out[21]
    DIRECTION OUTPUT ;
    USE SIGNAL ;
    PORT
      LAYER M1 ;
        RECT 909.5300 360.1550 910.0000 360.2450 ;
    END
  END out[21]
  PIN out[20]
    DIRECTION OUTPUT ;
    USE SIGNAL ;
    PORT
      LAYER M1 ;
        RECT 909.5300 358.5550 910.0000 358.6450 ;
    END
  END out[20]
  PIN out[19]
    DIRECTION OUTPUT ;
    USE SIGNAL ;
    PORT
      LAYER M1 ;
        RECT 909.5300 356.9550 910.0000 357.0450 ;
    END
  END out[19]
  PIN out[18]
    DIRECTION OUTPUT ;
    USE SIGNAL ;
    PORT
      LAYER M1 ;
        RECT 909.5300 355.3550 910.0000 355.4450 ;
    END
  END out[18]
  PIN out[17]
    DIRECTION OUTPUT ;
    USE SIGNAL ;
    PORT
      LAYER M1 ;
        RECT 909.5300 353.7550 910.0000 353.8450 ;
    END
  END out[17]
  PIN out[16]
    DIRECTION OUTPUT ;
    USE SIGNAL ;
    PORT
      LAYER M1 ;
        RECT 909.5300 352.1550 910.0000 352.2450 ;
    END
  END out[16]
  PIN out[15]
    DIRECTION OUTPUT ;
    USE SIGNAL ;
    PORT
      LAYER M1 ;
        RECT 909.5300 350.5550 910.0000 350.6450 ;
    END
  END out[15]
  PIN out[14]
    DIRECTION OUTPUT ;
    USE SIGNAL ;
    PORT
      LAYER M1 ;
        RECT 909.5300 348.9550 910.0000 349.0450 ;
    END
  END out[14]
  PIN out[13]
    DIRECTION OUTPUT ;
    USE SIGNAL ;
    PORT
      LAYER M1 ;
        RECT 909.5300 347.3550 910.0000 347.4450 ;
    END
  END out[13]
  PIN out[12]
    DIRECTION OUTPUT ;
    USE SIGNAL ;
    PORT
      LAYER M1 ;
        RECT 909.5300 345.7550 910.0000 345.8450 ;
    END
  END out[12]
  PIN out[11]
    DIRECTION OUTPUT ;
    USE SIGNAL ;
    PORT
      LAYER M1 ;
        RECT 909.5300 344.1550 910.0000 344.2450 ;
    END
  END out[11]
  PIN out[10]
    DIRECTION OUTPUT ;
    USE SIGNAL ;
    PORT
      LAYER M1 ;
        RECT 909.5300 342.5550 910.0000 342.6450 ;
    END
  END out[10]
  PIN out[9]
    DIRECTION OUTPUT ;
    USE SIGNAL ;
    PORT
      LAYER M1 ;
        RECT 909.5300 340.9550 910.0000 341.0450 ;
    END
  END out[9]
  PIN out[8]
    DIRECTION OUTPUT ;
    USE SIGNAL ;
    PORT
      LAYER M1 ;
        RECT 909.5300 339.3550 910.0000 339.4450 ;
    END
  END out[8]
  PIN out[7]
    DIRECTION OUTPUT ;
    USE SIGNAL ;
    PORT
      LAYER M1 ;
        RECT 909.5300 337.7550 910.0000 337.8450 ;
    END
  END out[7]
  PIN out[6]
    DIRECTION OUTPUT ;
    USE SIGNAL ;
    PORT
      LAYER M1 ;
        RECT 909.5300 336.1550 910.0000 336.2450 ;
    END
  END out[6]
  PIN out[5]
    DIRECTION OUTPUT ;
    USE SIGNAL ;
    PORT
      LAYER M1 ;
        RECT 909.5300 334.5550 910.0000 334.6450 ;
    END
  END out[5]
  PIN out[4]
    DIRECTION OUTPUT ;
    USE SIGNAL ;
    PORT
      LAYER M1 ;
        RECT 909.5300 332.9550 910.0000 333.0450 ;
    END
  END out[4]
  PIN out[3]
    DIRECTION OUTPUT ;
    USE SIGNAL ;
    PORT
      LAYER M1 ;
        RECT 909.5300 331.3550 910.0000 331.4450 ;
    END
  END out[3]
  PIN out[2]
    DIRECTION OUTPUT ;
    USE SIGNAL ;
    PORT
      LAYER M1 ;
        RECT 909.5300 329.7550 910.0000 329.8450 ;
    END
  END out[2]
  PIN out[1]
    DIRECTION OUTPUT ;
    USE SIGNAL ;
    PORT
      LAYER M1 ;
        RECT 909.5300 328.1550 910.0000 328.2450 ;
    END
  END out[1]
  PIN out[0]
    DIRECTION OUTPUT ;
    USE SIGNAL ;
    PORT
      LAYER M1 ;
        RECT 909.5300 326.5550 910.0000 326.6450 ;
    END
  END out[0]
  PIN reset
    DIRECTION INPUT ;
    USE SIGNAL ;
    PORT
      LAYER M1 ;
        RECT 0.0000 389.5550 0.4700 389.6450 ;
    END
  END reset
  OBS
    LAYER M1 ;
      RECT 0.0000 581.1350 910.0000 907.4000 ;
      RECT 0.0000 580.8650 909.4400 581.1350 ;
      RECT 0.0000 579.5350 910.0000 580.8650 ;
      RECT 0.0000 579.2650 909.4400 579.5350 ;
      RECT 0.0000 577.9350 910.0000 579.2650 ;
      RECT 0.0000 577.6650 909.4400 577.9350 ;
      RECT 0.0000 576.3350 910.0000 577.6650 ;
      RECT 0.0000 576.0650 909.4400 576.3350 ;
      RECT 0.0000 574.7350 910.0000 576.0650 ;
      RECT 0.0000 574.4650 909.4400 574.7350 ;
      RECT 0.0000 573.1350 910.0000 574.4650 ;
      RECT 0.0000 572.8650 909.4400 573.1350 ;
      RECT 0.0000 571.5350 910.0000 572.8650 ;
      RECT 0.0000 571.2650 909.4400 571.5350 ;
      RECT 0.0000 569.9350 910.0000 571.2650 ;
      RECT 0.0000 569.6650 909.4400 569.9350 ;
      RECT 0.0000 568.3350 910.0000 569.6650 ;
      RECT 0.0000 568.0650 909.4400 568.3350 ;
      RECT 0.0000 566.7350 910.0000 568.0650 ;
      RECT 0.0000 566.4650 909.4400 566.7350 ;
      RECT 0.0000 565.1350 910.0000 566.4650 ;
      RECT 0.0000 564.8650 909.4400 565.1350 ;
      RECT 0.0000 563.5350 910.0000 564.8650 ;
      RECT 0.0000 563.2650 909.4400 563.5350 ;
      RECT 0.0000 561.9350 910.0000 563.2650 ;
      RECT 0.0000 561.6650 909.4400 561.9350 ;
      RECT 0.0000 560.3350 910.0000 561.6650 ;
      RECT 0.0000 560.0650 909.4400 560.3350 ;
      RECT 0.0000 558.7350 910.0000 560.0650 ;
      RECT 0.0000 558.4650 909.4400 558.7350 ;
      RECT 0.0000 557.1350 910.0000 558.4650 ;
      RECT 0.0000 556.8650 909.4400 557.1350 ;
      RECT 0.0000 555.5350 910.0000 556.8650 ;
      RECT 0.0000 555.2650 909.4400 555.5350 ;
      RECT 0.0000 553.9350 910.0000 555.2650 ;
      RECT 0.0000 553.6650 909.4400 553.9350 ;
      RECT 0.0000 552.3350 910.0000 553.6650 ;
      RECT 0.0000 552.0650 909.4400 552.3350 ;
      RECT 0.0000 550.7350 910.0000 552.0650 ;
      RECT 0.0000 550.4650 909.4400 550.7350 ;
      RECT 0.0000 549.1350 910.0000 550.4650 ;
      RECT 0.0000 548.8650 909.4400 549.1350 ;
      RECT 0.0000 547.5350 910.0000 548.8650 ;
      RECT 0.0000 547.2650 909.4400 547.5350 ;
      RECT 0.0000 545.9350 910.0000 547.2650 ;
      RECT 0.0000 545.6650 909.4400 545.9350 ;
      RECT 0.0000 544.3350 910.0000 545.6650 ;
      RECT 0.0000 544.0650 909.4400 544.3350 ;
      RECT 0.0000 542.7350 910.0000 544.0650 ;
      RECT 0.0000 542.4650 909.4400 542.7350 ;
      RECT 0.0000 541.1350 910.0000 542.4650 ;
      RECT 0.0000 540.8650 909.4400 541.1350 ;
      RECT 0.0000 539.5350 910.0000 540.8650 ;
      RECT 0.0000 539.2650 909.4400 539.5350 ;
      RECT 0.0000 537.9350 910.0000 539.2650 ;
      RECT 0.0000 537.6650 909.4400 537.9350 ;
      RECT 0.0000 536.3350 910.0000 537.6650 ;
      RECT 0.0000 536.0650 909.4400 536.3350 ;
      RECT 0.0000 534.7350 910.0000 536.0650 ;
      RECT 0.0000 534.4650 909.4400 534.7350 ;
      RECT 0.0000 533.1350 910.0000 534.4650 ;
      RECT 0.0000 532.8650 909.4400 533.1350 ;
      RECT 0.0000 531.5350 910.0000 532.8650 ;
      RECT 0.0000 531.2650 909.4400 531.5350 ;
      RECT 0.0000 529.9350 910.0000 531.2650 ;
      RECT 0.0000 529.6650 909.4400 529.9350 ;
      RECT 0.0000 528.3350 910.0000 529.6650 ;
      RECT 0.0000 528.0650 909.4400 528.3350 ;
      RECT 0.0000 526.7350 910.0000 528.0650 ;
      RECT 0.0000 526.4650 909.4400 526.7350 ;
      RECT 0.0000 525.1350 910.0000 526.4650 ;
      RECT 0.0000 524.8650 909.4400 525.1350 ;
      RECT 0.0000 523.5350 910.0000 524.8650 ;
      RECT 0.0000 523.2650 909.4400 523.5350 ;
      RECT 0.0000 521.9350 910.0000 523.2650 ;
      RECT 0.0000 521.6650 909.4400 521.9350 ;
      RECT 0.0000 520.3350 910.0000 521.6650 ;
      RECT 0.0000 520.0650 909.4400 520.3350 ;
      RECT 0.0000 519.3350 910.0000 520.0650 ;
      RECT 0.5600 519.0650 910.0000 519.3350 ;
      RECT 0.0000 518.7350 910.0000 519.0650 ;
      RECT 0.0000 518.4650 909.4400 518.7350 ;
      RECT 0.0000 517.7350 910.0000 518.4650 ;
      RECT 0.5600 517.4650 910.0000 517.7350 ;
      RECT 0.0000 517.1350 910.0000 517.4650 ;
      RECT 0.0000 516.8650 909.4400 517.1350 ;
      RECT 0.0000 516.1350 910.0000 516.8650 ;
      RECT 0.5600 515.8650 910.0000 516.1350 ;
      RECT 0.0000 515.5350 910.0000 515.8650 ;
      RECT 0.0000 515.2650 909.4400 515.5350 ;
      RECT 0.0000 514.5350 910.0000 515.2650 ;
      RECT 0.5600 514.2650 910.0000 514.5350 ;
      RECT 0.0000 513.9350 910.0000 514.2650 ;
      RECT 0.0000 513.6650 909.4400 513.9350 ;
      RECT 0.0000 512.9350 910.0000 513.6650 ;
      RECT 0.5600 512.6650 910.0000 512.9350 ;
      RECT 0.0000 512.3350 910.0000 512.6650 ;
      RECT 0.0000 512.0650 909.4400 512.3350 ;
      RECT 0.0000 511.3350 910.0000 512.0650 ;
      RECT 0.5600 511.0650 910.0000 511.3350 ;
      RECT 0.0000 510.7350 910.0000 511.0650 ;
      RECT 0.0000 510.4650 909.4400 510.7350 ;
      RECT 0.0000 509.7350 910.0000 510.4650 ;
      RECT 0.5600 509.4650 910.0000 509.7350 ;
      RECT 0.0000 509.1350 910.0000 509.4650 ;
      RECT 0.0000 508.8650 909.4400 509.1350 ;
      RECT 0.0000 508.1350 910.0000 508.8650 ;
      RECT 0.5600 507.8650 910.0000 508.1350 ;
      RECT 0.0000 507.5350 910.0000 507.8650 ;
      RECT 0.0000 507.2650 909.4400 507.5350 ;
      RECT 0.0000 506.5350 910.0000 507.2650 ;
      RECT 0.5600 506.2650 910.0000 506.5350 ;
      RECT 0.0000 505.9350 910.0000 506.2650 ;
      RECT 0.0000 505.6650 909.4400 505.9350 ;
      RECT 0.0000 504.9350 910.0000 505.6650 ;
      RECT 0.5600 504.6650 910.0000 504.9350 ;
      RECT 0.0000 504.3350 910.0000 504.6650 ;
      RECT 0.0000 504.0650 909.4400 504.3350 ;
      RECT 0.0000 503.3350 910.0000 504.0650 ;
      RECT 0.5600 503.0650 910.0000 503.3350 ;
      RECT 0.0000 502.7350 910.0000 503.0650 ;
      RECT 0.0000 502.4650 909.4400 502.7350 ;
      RECT 0.0000 501.7350 910.0000 502.4650 ;
      RECT 0.5600 501.4650 910.0000 501.7350 ;
      RECT 0.0000 501.1350 910.0000 501.4650 ;
      RECT 0.0000 500.8650 909.4400 501.1350 ;
      RECT 0.0000 500.1350 910.0000 500.8650 ;
      RECT 0.5600 499.8650 910.0000 500.1350 ;
      RECT 0.0000 499.5350 910.0000 499.8650 ;
      RECT 0.0000 499.2650 909.4400 499.5350 ;
      RECT 0.0000 498.5350 910.0000 499.2650 ;
      RECT 0.5600 498.2650 910.0000 498.5350 ;
      RECT 0.0000 497.9350 910.0000 498.2650 ;
      RECT 0.0000 497.6650 909.4400 497.9350 ;
      RECT 0.0000 496.9350 910.0000 497.6650 ;
      RECT 0.5600 496.6650 910.0000 496.9350 ;
      RECT 0.0000 496.3350 910.0000 496.6650 ;
      RECT 0.0000 496.0650 909.4400 496.3350 ;
      RECT 0.0000 495.3350 910.0000 496.0650 ;
      RECT 0.5600 495.0650 910.0000 495.3350 ;
      RECT 0.0000 494.7350 910.0000 495.0650 ;
      RECT 0.0000 494.4650 909.4400 494.7350 ;
      RECT 0.0000 493.7350 910.0000 494.4650 ;
      RECT 0.5600 493.4650 910.0000 493.7350 ;
      RECT 0.0000 493.1350 910.0000 493.4650 ;
      RECT 0.0000 492.8650 909.4400 493.1350 ;
      RECT 0.0000 492.1350 910.0000 492.8650 ;
      RECT 0.5600 491.8650 910.0000 492.1350 ;
      RECT 0.0000 491.5350 910.0000 491.8650 ;
      RECT 0.0000 491.2650 909.4400 491.5350 ;
      RECT 0.0000 490.5350 910.0000 491.2650 ;
      RECT 0.5600 490.2650 910.0000 490.5350 ;
      RECT 0.0000 489.9350 910.0000 490.2650 ;
      RECT 0.0000 489.6650 909.4400 489.9350 ;
      RECT 0.0000 488.9350 910.0000 489.6650 ;
      RECT 0.5600 488.6650 910.0000 488.9350 ;
      RECT 0.0000 488.3350 910.0000 488.6650 ;
      RECT 0.0000 488.0650 909.4400 488.3350 ;
      RECT 0.0000 487.3350 910.0000 488.0650 ;
      RECT 0.5600 487.0650 910.0000 487.3350 ;
      RECT 0.0000 486.7350 910.0000 487.0650 ;
      RECT 0.0000 486.4650 909.4400 486.7350 ;
      RECT 0.0000 485.7350 910.0000 486.4650 ;
      RECT 0.5600 485.4650 910.0000 485.7350 ;
      RECT 0.0000 485.1350 910.0000 485.4650 ;
      RECT 0.0000 484.8650 909.4400 485.1350 ;
      RECT 0.0000 484.1350 910.0000 484.8650 ;
      RECT 0.5600 483.8650 910.0000 484.1350 ;
      RECT 0.0000 483.5350 910.0000 483.8650 ;
      RECT 0.0000 483.2650 909.4400 483.5350 ;
      RECT 0.0000 482.5350 910.0000 483.2650 ;
      RECT 0.5600 482.2650 910.0000 482.5350 ;
      RECT 0.0000 481.9350 910.0000 482.2650 ;
      RECT 0.0000 481.6650 909.4400 481.9350 ;
      RECT 0.0000 480.9350 910.0000 481.6650 ;
      RECT 0.5600 480.6650 910.0000 480.9350 ;
      RECT 0.0000 480.3350 910.0000 480.6650 ;
      RECT 0.0000 480.0650 909.4400 480.3350 ;
      RECT 0.0000 479.3350 910.0000 480.0650 ;
      RECT 0.5600 479.0650 910.0000 479.3350 ;
      RECT 0.0000 478.7350 910.0000 479.0650 ;
      RECT 0.0000 478.4650 909.4400 478.7350 ;
      RECT 0.0000 477.7350 910.0000 478.4650 ;
      RECT 0.5600 477.4650 910.0000 477.7350 ;
      RECT 0.0000 477.1350 910.0000 477.4650 ;
      RECT 0.0000 476.8650 909.4400 477.1350 ;
      RECT 0.0000 476.1350 910.0000 476.8650 ;
      RECT 0.5600 475.8650 910.0000 476.1350 ;
      RECT 0.0000 475.5350 910.0000 475.8650 ;
      RECT 0.0000 475.2650 909.4400 475.5350 ;
      RECT 0.0000 474.5350 910.0000 475.2650 ;
      RECT 0.5600 474.2650 910.0000 474.5350 ;
      RECT 0.0000 473.9350 910.0000 474.2650 ;
      RECT 0.0000 473.6650 909.4400 473.9350 ;
      RECT 0.0000 472.9350 910.0000 473.6650 ;
      RECT 0.5600 472.6650 910.0000 472.9350 ;
      RECT 0.0000 472.3350 910.0000 472.6650 ;
      RECT 0.0000 472.0650 909.4400 472.3350 ;
      RECT 0.0000 471.3350 910.0000 472.0650 ;
      RECT 0.5600 471.0650 910.0000 471.3350 ;
      RECT 0.0000 470.7350 910.0000 471.0650 ;
      RECT 0.0000 470.4650 909.4400 470.7350 ;
      RECT 0.0000 469.7350 910.0000 470.4650 ;
      RECT 0.5600 469.4650 910.0000 469.7350 ;
      RECT 0.0000 469.1350 910.0000 469.4650 ;
      RECT 0.0000 468.8650 909.4400 469.1350 ;
      RECT 0.0000 468.1350 910.0000 468.8650 ;
      RECT 0.5600 467.8650 910.0000 468.1350 ;
      RECT 0.0000 467.5350 910.0000 467.8650 ;
      RECT 0.0000 467.2650 909.4400 467.5350 ;
      RECT 0.0000 466.5350 910.0000 467.2650 ;
      RECT 0.5600 466.2650 910.0000 466.5350 ;
      RECT 0.0000 465.9350 910.0000 466.2650 ;
      RECT 0.0000 465.6650 909.4400 465.9350 ;
      RECT 0.0000 464.9350 910.0000 465.6650 ;
      RECT 0.5600 464.6650 910.0000 464.9350 ;
      RECT 0.0000 464.3350 910.0000 464.6650 ;
      RECT 0.0000 464.0650 909.4400 464.3350 ;
      RECT 0.0000 463.3350 910.0000 464.0650 ;
      RECT 0.5600 463.0650 910.0000 463.3350 ;
      RECT 0.0000 462.7350 910.0000 463.0650 ;
      RECT 0.0000 462.4650 909.4400 462.7350 ;
      RECT 0.0000 461.7350 910.0000 462.4650 ;
      RECT 0.5600 461.4650 910.0000 461.7350 ;
      RECT 0.0000 461.1350 910.0000 461.4650 ;
      RECT 0.0000 460.8650 909.4400 461.1350 ;
      RECT 0.0000 460.1350 910.0000 460.8650 ;
      RECT 0.5600 459.8650 910.0000 460.1350 ;
      RECT 0.0000 459.5350 910.0000 459.8650 ;
      RECT 0.0000 459.2650 909.4400 459.5350 ;
      RECT 0.0000 458.5350 910.0000 459.2650 ;
      RECT 0.5600 458.2650 910.0000 458.5350 ;
      RECT 0.0000 457.9350 910.0000 458.2650 ;
      RECT 0.0000 457.6650 909.4400 457.9350 ;
      RECT 0.0000 456.9350 910.0000 457.6650 ;
      RECT 0.5600 456.6650 910.0000 456.9350 ;
      RECT 0.0000 456.3350 910.0000 456.6650 ;
      RECT 0.0000 456.0650 909.4400 456.3350 ;
      RECT 0.0000 455.3350 910.0000 456.0650 ;
      RECT 0.5600 455.0650 910.0000 455.3350 ;
      RECT 0.0000 454.7350 910.0000 455.0650 ;
      RECT 0.0000 454.4650 909.4400 454.7350 ;
      RECT 0.0000 453.7350 910.0000 454.4650 ;
      RECT 0.5600 453.4650 910.0000 453.7350 ;
      RECT 0.0000 453.1350 910.0000 453.4650 ;
      RECT 0.0000 452.8650 909.4400 453.1350 ;
      RECT 0.0000 452.1350 910.0000 452.8650 ;
      RECT 0.5600 451.8650 910.0000 452.1350 ;
      RECT 0.0000 451.5350 910.0000 451.8650 ;
      RECT 0.0000 451.2650 909.4400 451.5350 ;
      RECT 0.0000 450.5350 910.0000 451.2650 ;
      RECT 0.5600 450.2650 910.0000 450.5350 ;
      RECT 0.0000 449.9350 910.0000 450.2650 ;
      RECT 0.0000 449.6650 909.4400 449.9350 ;
      RECT 0.0000 448.9350 910.0000 449.6650 ;
      RECT 0.5600 448.6650 910.0000 448.9350 ;
      RECT 0.0000 448.3350 910.0000 448.6650 ;
      RECT 0.0000 448.0650 909.4400 448.3350 ;
      RECT 0.0000 447.3350 910.0000 448.0650 ;
      RECT 0.5600 447.0650 910.0000 447.3350 ;
      RECT 0.0000 446.7350 910.0000 447.0650 ;
      RECT 0.0000 446.4650 909.4400 446.7350 ;
      RECT 0.0000 445.7350 910.0000 446.4650 ;
      RECT 0.5600 445.4650 910.0000 445.7350 ;
      RECT 0.0000 445.1350 910.0000 445.4650 ;
      RECT 0.0000 444.8650 909.4400 445.1350 ;
      RECT 0.0000 444.1350 910.0000 444.8650 ;
      RECT 0.5600 443.8650 910.0000 444.1350 ;
      RECT 0.0000 443.5350 910.0000 443.8650 ;
      RECT 0.0000 443.2650 909.4400 443.5350 ;
      RECT 0.0000 442.5350 910.0000 443.2650 ;
      RECT 0.5600 442.2650 910.0000 442.5350 ;
      RECT 0.0000 441.9350 910.0000 442.2650 ;
      RECT 0.0000 441.6650 909.4400 441.9350 ;
      RECT 0.0000 440.9350 910.0000 441.6650 ;
      RECT 0.5600 440.6650 910.0000 440.9350 ;
      RECT 0.0000 440.3350 910.0000 440.6650 ;
      RECT 0.0000 440.0650 909.4400 440.3350 ;
      RECT 0.0000 439.3350 910.0000 440.0650 ;
      RECT 0.5600 439.0650 910.0000 439.3350 ;
      RECT 0.0000 438.7350 910.0000 439.0650 ;
      RECT 0.0000 438.4650 909.4400 438.7350 ;
      RECT 0.0000 437.7350 910.0000 438.4650 ;
      RECT 0.5600 437.4650 910.0000 437.7350 ;
      RECT 0.0000 437.1350 910.0000 437.4650 ;
      RECT 0.0000 436.8650 909.4400 437.1350 ;
      RECT 0.0000 436.1350 910.0000 436.8650 ;
      RECT 0.5600 435.8650 910.0000 436.1350 ;
      RECT 0.0000 435.5350 910.0000 435.8650 ;
      RECT 0.0000 435.2650 909.4400 435.5350 ;
      RECT 0.0000 434.5350 910.0000 435.2650 ;
      RECT 0.5600 434.2650 910.0000 434.5350 ;
      RECT 0.0000 433.9350 910.0000 434.2650 ;
      RECT 0.0000 433.6650 909.4400 433.9350 ;
      RECT 0.0000 432.9350 910.0000 433.6650 ;
      RECT 0.5600 432.6650 910.0000 432.9350 ;
      RECT 0.0000 432.3350 910.0000 432.6650 ;
      RECT 0.0000 432.0650 909.4400 432.3350 ;
      RECT 0.0000 431.3350 910.0000 432.0650 ;
      RECT 0.5600 431.0650 910.0000 431.3350 ;
      RECT 0.0000 430.7350 910.0000 431.0650 ;
      RECT 0.0000 430.4650 909.4400 430.7350 ;
      RECT 0.0000 429.7350 910.0000 430.4650 ;
      RECT 0.5600 429.4650 910.0000 429.7350 ;
      RECT 0.0000 429.1350 910.0000 429.4650 ;
      RECT 0.0000 428.8650 909.4400 429.1350 ;
      RECT 0.0000 428.1350 910.0000 428.8650 ;
      RECT 0.5600 427.8650 910.0000 428.1350 ;
      RECT 0.0000 427.5350 910.0000 427.8650 ;
      RECT 0.0000 427.2650 909.4400 427.5350 ;
      RECT 0.0000 426.5350 910.0000 427.2650 ;
      RECT 0.5600 426.2650 910.0000 426.5350 ;
      RECT 0.0000 425.9350 910.0000 426.2650 ;
      RECT 0.0000 425.6650 909.4400 425.9350 ;
      RECT 0.0000 424.9350 910.0000 425.6650 ;
      RECT 0.5600 424.6650 910.0000 424.9350 ;
      RECT 0.0000 424.3350 910.0000 424.6650 ;
      RECT 0.0000 424.0650 909.4400 424.3350 ;
      RECT 0.0000 423.3350 910.0000 424.0650 ;
      RECT 0.5600 423.0650 910.0000 423.3350 ;
      RECT 0.0000 422.7350 910.0000 423.0650 ;
      RECT 0.0000 422.4650 909.4400 422.7350 ;
      RECT 0.0000 421.7350 910.0000 422.4650 ;
      RECT 0.5600 421.4650 910.0000 421.7350 ;
      RECT 0.0000 421.1350 910.0000 421.4650 ;
      RECT 0.0000 420.8650 909.4400 421.1350 ;
      RECT 0.0000 420.1350 910.0000 420.8650 ;
      RECT 0.5600 419.8650 910.0000 420.1350 ;
      RECT 0.0000 419.5350 910.0000 419.8650 ;
      RECT 0.0000 419.2650 909.4400 419.5350 ;
      RECT 0.0000 418.5350 910.0000 419.2650 ;
      RECT 0.5600 418.2650 910.0000 418.5350 ;
      RECT 0.0000 417.9350 910.0000 418.2650 ;
      RECT 0.0000 417.6650 909.4400 417.9350 ;
      RECT 0.0000 416.9350 910.0000 417.6650 ;
      RECT 0.5600 416.6650 910.0000 416.9350 ;
      RECT 0.0000 416.3350 910.0000 416.6650 ;
      RECT 0.0000 416.0650 909.4400 416.3350 ;
      RECT 0.0000 415.3350 910.0000 416.0650 ;
      RECT 0.5600 415.0650 910.0000 415.3350 ;
      RECT 0.0000 414.7350 910.0000 415.0650 ;
      RECT 0.0000 414.4650 909.4400 414.7350 ;
      RECT 0.0000 413.7350 910.0000 414.4650 ;
      RECT 0.5600 413.4650 910.0000 413.7350 ;
      RECT 0.0000 413.1350 910.0000 413.4650 ;
      RECT 0.0000 412.8650 909.4400 413.1350 ;
      RECT 0.0000 412.1350 910.0000 412.8650 ;
      RECT 0.5600 411.8650 910.0000 412.1350 ;
      RECT 0.0000 411.5350 910.0000 411.8650 ;
      RECT 0.0000 411.2650 909.4400 411.5350 ;
      RECT 0.0000 410.5350 910.0000 411.2650 ;
      RECT 0.5600 410.2650 910.0000 410.5350 ;
      RECT 0.0000 409.9350 910.0000 410.2650 ;
      RECT 0.0000 409.6650 909.4400 409.9350 ;
      RECT 0.0000 408.9350 910.0000 409.6650 ;
      RECT 0.5600 408.6650 910.0000 408.9350 ;
      RECT 0.0000 408.3350 910.0000 408.6650 ;
      RECT 0.0000 408.0650 909.4400 408.3350 ;
      RECT 0.0000 407.3350 910.0000 408.0650 ;
      RECT 0.5600 407.0650 910.0000 407.3350 ;
      RECT 0.0000 406.7350 910.0000 407.0650 ;
      RECT 0.0000 406.4650 909.4400 406.7350 ;
      RECT 0.0000 405.7350 910.0000 406.4650 ;
      RECT 0.5600 405.4650 910.0000 405.7350 ;
      RECT 0.0000 405.1350 910.0000 405.4650 ;
      RECT 0.0000 404.8650 909.4400 405.1350 ;
      RECT 0.0000 404.1350 910.0000 404.8650 ;
      RECT 0.5600 403.8650 910.0000 404.1350 ;
      RECT 0.0000 403.5350 910.0000 403.8650 ;
      RECT 0.0000 403.2650 909.4400 403.5350 ;
      RECT 0.0000 402.5350 910.0000 403.2650 ;
      RECT 0.5600 402.2650 910.0000 402.5350 ;
      RECT 0.0000 401.9350 910.0000 402.2650 ;
      RECT 0.0000 401.6650 909.4400 401.9350 ;
      RECT 0.0000 400.9350 910.0000 401.6650 ;
      RECT 0.5600 400.6650 910.0000 400.9350 ;
      RECT 0.0000 400.3350 910.0000 400.6650 ;
      RECT 0.0000 400.0650 909.4400 400.3350 ;
      RECT 0.0000 399.3350 910.0000 400.0650 ;
      RECT 0.5600 399.0650 910.0000 399.3350 ;
      RECT 0.0000 398.7350 910.0000 399.0650 ;
      RECT 0.0000 398.4650 909.4400 398.7350 ;
      RECT 0.0000 397.7350 910.0000 398.4650 ;
      RECT 0.5600 397.4650 910.0000 397.7350 ;
      RECT 0.0000 397.1350 910.0000 397.4650 ;
      RECT 0.0000 396.8650 909.4400 397.1350 ;
      RECT 0.0000 396.1350 910.0000 396.8650 ;
      RECT 0.5600 395.8650 910.0000 396.1350 ;
      RECT 0.0000 395.5350 910.0000 395.8650 ;
      RECT 0.0000 395.2650 909.4400 395.5350 ;
      RECT 0.0000 394.5350 910.0000 395.2650 ;
      RECT 0.5600 394.2650 910.0000 394.5350 ;
      RECT 0.0000 393.9350 910.0000 394.2650 ;
      RECT 0.0000 393.6650 909.4400 393.9350 ;
      RECT 0.0000 392.9350 910.0000 393.6650 ;
      RECT 0.5600 392.6650 910.0000 392.9350 ;
      RECT 0.0000 392.3350 910.0000 392.6650 ;
      RECT 0.0000 392.0650 909.4400 392.3350 ;
      RECT 0.0000 391.3350 910.0000 392.0650 ;
      RECT 0.5600 391.0650 910.0000 391.3350 ;
      RECT 0.0000 390.7350 910.0000 391.0650 ;
      RECT 0.0000 390.4650 909.4400 390.7350 ;
      RECT 0.0000 389.7350 910.0000 390.4650 ;
      RECT 0.5600 389.4650 910.0000 389.7350 ;
      RECT 0.0000 389.1350 910.0000 389.4650 ;
      RECT 0.0000 388.8650 909.4400 389.1350 ;
      RECT 0.0000 388.1350 910.0000 388.8650 ;
      RECT 0.5600 387.8650 910.0000 388.1350 ;
      RECT 0.0000 387.5350 910.0000 387.8650 ;
      RECT 0.0000 387.2650 909.4400 387.5350 ;
      RECT 0.0000 385.9350 910.0000 387.2650 ;
      RECT 0.0000 385.6650 909.4400 385.9350 ;
      RECT 0.0000 384.3350 910.0000 385.6650 ;
      RECT 0.0000 384.0650 909.4400 384.3350 ;
      RECT 0.0000 382.7350 910.0000 384.0650 ;
      RECT 0.0000 382.4650 909.4400 382.7350 ;
      RECT 0.0000 381.1350 910.0000 382.4650 ;
      RECT 0.0000 380.8650 909.4400 381.1350 ;
      RECT 0.0000 379.5350 910.0000 380.8650 ;
      RECT 0.0000 379.2650 909.4400 379.5350 ;
      RECT 0.0000 377.9350 910.0000 379.2650 ;
      RECT 0.0000 377.6650 909.4400 377.9350 ;
      RECT 0.0000 376.3350 910.0000 377.6650 ;
      RECT 0.0000 376.0650 909.4400 376.3350 ;
      RECT 0.0000 374.7350 910.0000 376.0650 ;
      RECT 0.0000 374.4650 909.4400 374.7350 ;
      RECT 0.0000 373.1350 910.0000 374.4650 ;
      RECT 0.0000 372.8650 909.4400 373.1350 ;
      RECT 0.0000 371.5350 910.0000 372.8650 ;
      RECT 0.0000 371.2650 909.4400 371.5350 ;
      RECT 0.0000 369.9350 910.0000 371.2650 ;
      RECT 0.0000 369.6650 909.4400 369.9350 ;
      RECT 0.0000 368.3350 910.0000 369.6650 ;
      RECT 0.0000 368.0650 909.4400 368.3350 ;
      RECT 0.0000 366.7350 910.0000 368.0650 ;
      RECT 0.0000 366.4650 909.4400 366.7350 ;
      RECT 0.0000 365.1350 910.0000 366.4650 ;
      RECT 0.0000 364.8650 909.4400 365.1350 ;
      RECT 0.0000 363.5350 910.0000 364.8650 ;
      RECT 0.0000 363.2650 909.4400 363.5350 ;
      RECT 0.0000 361.9350 910.0000 363.2650 ;
      RECT 0.0000 361.6650 909.4400 361.9350 ;
      RECT 0.0000 360.3350 910.0000 361.6650 ;
      RECT 0.0000 360.0650 909.4400 360.3350 ;
      RECT 0.0000 358.7350 910.0000 360.0650 ;
      RECT 0.0000 358.4650 909.4400 358.7350 ;
      RECT 0.0000 357.1350 910.0000 358.4650 ;
      RECT 0.0000 356.8650 909.4400 357.1350 ;
      RECT 0.0000 355.5350 910.0000 356.8650 ;
      RECT 0.0000 355.2650 909.4400 355.5350 ;
      RECT 0.0000 353.9350 910.0000 355.2650 ;
      RECT 0.0000 353.6650 909.4400 353.9350 ;
      RECT 0.0000 352.3350 910.0000 353.6650 ;
      RECT 0.0000 352.0650 909.4400 352.3350 ;
      RECT 0.0000 350.7350 910.0000 352.0650 ;
      RECT 0.0000 350.4650 909.4400 350.7350 ;
      RECT 0.0000 349.1350 910.0000 350.4650 ;
      RECT 0.0000 348.8650 909.4400 349.1350 ;
      RECT 0.0000 347.5350 910.0000 348.8650 ;
      RECT 0.0000 347.2650 909.4400 347.5350 ;
      RECT 0.0000 345.9350 910.0000 347.2650 ;
      RECT 0.0000 345.6650 909.4400 345.9350 ;
      RECT 0.0000 344.3350 910.0000 345.6650 ;
      RECT 0.0000 344.0650 909.4400 344.3350 ;
      RECT 0.0000 342.7350 910.0000 344.0650 ;
      RECT 0.0000 342.4650 909.4400 342.7350 ;
      RECT 0.0000 341.1350 910.0000 342.4650 ;
      RECT 0.0000 340.8650 909.4400 341.1350 ;
      RECT 0.0000 339.5350 910.0000 340.8650 ;
      RECT 0.0000 339.2650 909.4400 339.5350 ;
      RECT 0.0000 337.9350 910.0000 339.2650 ;
      RECT 0.0000 337.6650 909.4400 337.9350 ;
      RECT 0.0000 336.3350 910.0000 337.6650 ;
      RECT 0.0000 336.0650 909.4400 336.3350 ;
      RECT 0.0000 334.7350 910.0000 336.0650 ;
      RECT 0.0000 334.4650 909.4400 334.7350 ;
      RECT 0.0000 333.1350 910.0000 334.4650 ;
      RECT 0.0000 332.8650 909.4400 333.1350 ;
      RECT 0.0000 331.5350 910.0000 332.8650 ;
      RECT 0.0000 331.2650 909.4400 331.5350 ;
      RECT 0.0000 329.9350 910.0000 331.2650 ;
      RECT 0.0000 329.6650 909.4400 329.9350 ;
      RECT 0.0000 328.3350 910.0000 329.6650 ;
      RECT 0.0000 328.0650 909.4400 328.3350 ;
      RECT 0.0000 326.7350 910.0000 328.0650 ;
      RECT 0.0000 326.4650 909.4400 326.7350 ;
      RECT 0.0000 0.0000 910.0000 326.4650 ;
    LAYER M2 ;
      RECT 0.0000 0.0000 910.0000 907.4000 ;
    LAYER M3 ;
      RECT 0.0000 0.0000 910.0000 907.4000 ;
    LAYER M4 ;
      RECT 0.0000 0.0000 910.0000 907.4000 ;
    LAYER M5 ;
      RECT 0.0000 0.0000 910.0000 907.4000 ;
    LAYER M6 ;
      RECT 0.0000 0.0000 910.0000 907.4000 ;
    LAYER M7 ;
      RECT 0.0000 0.0000 910.0000 907.4000 ;
    LAYER M8 ;
      RECT 0.0000 0.0000 910.0000 907.4000 ;
  END
END fullchip

END LIBRARY
